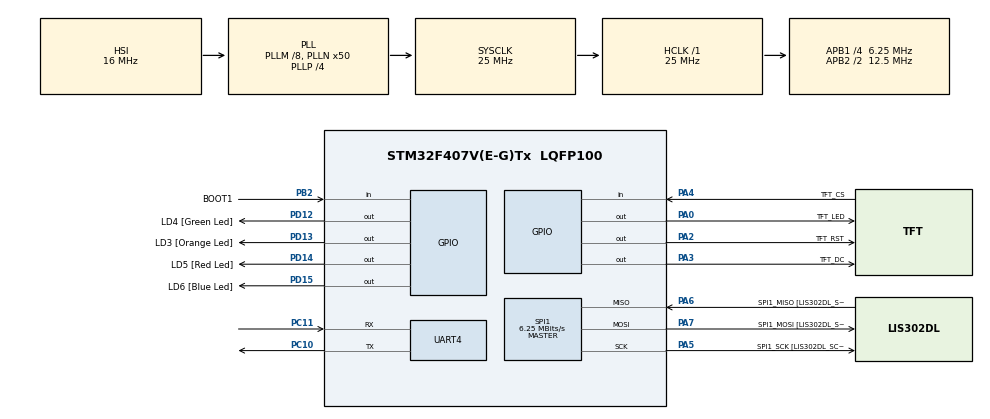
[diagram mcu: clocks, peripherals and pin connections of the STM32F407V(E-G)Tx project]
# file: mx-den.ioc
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Dma.Request0=SPI1_RX
Dma.Request1=SPI1_TX
Dma.SPI1_RX.0.Direction=DMA_PERIPH_TO_MEMORY
Dma.SPI1_RX.0.FIFOMode=DMA_FIFOMODE_DISABLE
Dma.SPI1_RX.0.Instance=DMA2_Stream2
Dma.SPI1_RX.0.MemDataAlignment=DMA_MDATAALIGN_BYTE
Dma.SPI1_RX.0.MemInc=DMA_MINC_ENABLE
Dma.SPI1_RX.0.Mode=DMA_NORMAL
Dma.SPI1_RX.0.PeriphDataAlignment=DMA_PDATAALIGN_BYTE
Dma.SPI1_RX.0.PeriphInc=DMA_PINC_DISABLE
Dma.SPI1_RX.0.Priority=DMA_PRIORITY_LOW
Dma.SPI1_TX.1.Direction=DMA_MEMORY_TO_PERIPH
Dma.SPI1_TX.1.FIFOMode=DMA_FIFOMODE_DISABLE
Dma.SPI1_TX.1.Instance=DMA2_Stream3
Dma.SPI1_TX.1.MemDataAlignment=DMA_MDATAALIGN_BYTE
Dma.SPI1_TX.1.MemInc=DMA_MINC_ENABLE
Dma.SPI1_TX.1.Mode=DMA_NORMAL
Dma.SPI1_TX.1.PeriphDataAlignment=DMA_PDATAALIGN_BYTE
Dma.SPI1_TX.1.PeriphInc=DMA_PINC_DISABLE
Dma.SPI1_TX.1.Priority=DMA_PRIORITY_LOW
Mcu.Family=STM32F4
Mcu.Name=STM32F407V(E-G)Tx
Mcu.Package=LQFP100
NVIC.DMA2_Stream2_IRQn=true\:0\:0\:false\:false\:true\:false\:true\:true
NVIC.DMA2_Stream3_IRQn=true\:0\:0\:false\:false\:true\:false\:true\:true
NVIC.PriorityGroup=NVIC_PRIORITYGROUP_0
NVIC.UART4_IRQn=true\:0\:1\:true\:false\:true\:true\:true\:true
PA0-WKUP.GPIO_Label=TFT_LED
PA0-WKUP.Signal=GPIO_Output
PA2.GPIO_Label=TFT_RST
PA2.Signal=GPIO_Output
PA3.GPIO_Label=TFT_DC
PA3.Signal=GPIO_Output
PA4.GPIO_Label=TFT_CS
PA4.Signal=GPIO_Input
PA5.GPIO_Label=SPI1_SCK [LIS302DL_SCL/SPC]
PA5.GPIO_Mode=GPIO_MODE_AF_PP
PA5.GPIO_PuPd=GPIO_NOPULL
PA5.GPIO_Speed=GPIO_SPEED_FREQ_LOW
PA5.Mode=Full_Duplex_Master
PA5.Signal=SPI1_SCK
PA6.GPIO_Label=SPI1_MISO [LIS302DL_SDO]
PA6.GPIO_Mode=GPIO_MODE_AF_PP
PA6.GPIO_PuPd=GPIO_NOPULL
PA6.GPIO_Speed=GPIO_SPEED_FREQ_LOW
PA6.Mode=Full_Duplex_Master
PA6.Signal=SPI1_MISO
PA7.GPIO_Label=SPI1_MOSI [LIS302DL_SDA/SDI/SDO]
PA7.GPIO_Mode=GPIO_MODE_AF_PP
PA7.GPIO_PuPd=GPIO_NOPULL
PA7.GPIO_Speed=GPIO_SPEED_FREQ_LOW
PA7.Mode=Full_Duplex_Master
PA7.Signal=SPI1_MOSI
PB2.GPIO_Label=BOOT1
PB2.GPIO_Mode=GPIO_MODE_INPUT
PB2.GPIO_PuPd=GPIO_NOPULL
PB2.Signal=GPIO_Input
PC10.Mode=Asynchronous
PC10.Signal=UART4_TX
PC11.Mode=Asynchronous
PC11.Signal=UART4_RX
PC14-OSC32_IN.GPIO_Label=PC14-OSC32_IN
PC14-OSC32_IN.Signal=RCC_OSC32_IN
PC15-OSC32_OUT.GPIO_Label=PC15-OSC32_OUT
PC15-OSC32_OUT.Signal=RCC_OSC32_OUT
PD12.GPIO_Label=LD4 [Green Led]
PD12.GPIO_PuPd=GPIO_NOPULL
PD12.GPIO_Speed=GPIO_SPEED_FREQ_LOW
PD12.Signal=GPIO_Output
PD13.GPIO_Label=LD3 [Orange Led]
PD13.GPIO_PuPd=GPIO_NOPULL
PD13.GPIO_Speed=GPIO_SPEED_FREQ_LOW
PD13.Signal=GPIO_Output
PD14.GPIO_Label=LD5 [Red Led]
PD14.GPIO_PuPd=GPIO_NOPULL
PD14.GPIO_Speed=GPIO_SPEED_FREQ_LOW
PD14.Signal=GPIO_Output
PD15.GPIO_Label=LD6 [Blue Led]
PD15.GPIO_PuPd=GPIO_NOPULL
PD15.GPIO_Speed=GPIO_SPEED_FREQ_LOW
PD15.Signal=GPIO_Output
PH0-OSC_IN.GPIO_Label=PH0-OSC_IN
PH0-OSC_IN.Signal=RCC_OSC_IN
PH1-OSC_OUT.GPIO_Label=PH1-OSC_OUT
PH1-OSC_OUT.Signal=RCC_OSC_OUT
ProjectManager.HeapSize=0x200
ProjectManager.StackSize=0x400
ProjectManager.TargetToolchain=EWARM V8.50
RCC.48MHZClocksFreq_Value=14285714.285714285
RCC.AHBFreq_Value=25000000
RCC.APB1CLKDivider=RCC_HCLK_DIV4
RCC.APB1Freq_Value=6250000
RCC.APB1TimFreq_Value=12500000
RCC.APB2CLKDivider=RCC_HCLK_DIV2
RCC.APB2Freq_Value=12500000
RCC.APB2TimFreq_Value=25000000
RCC.CortexFreq_Value=25000000
RCC.HCLKFreq_Value=25000000
RCC.HSE_VALUE=8000000
RCC.HSI_VALUE=16000000
RCC.LSE_VALUE=32768
RCC.PLLM=8
RCC.PLLN=50
RCC.PLLP=RCC_PLLP_DIV4
RCC.PLLQ=7
RCC.SYSCLKFreq_VALUE=25000000
RCC.SYSCLKSource=RCC_SYSCLKSOURCE_PLLCLK
RCC.VCOOutputFreq_Value=100000000
SPI1.CalculateBaudRate=6.25 MBits/s
SPI1.Direction=SPI_DIRECTION_2LINES
SPI1.Mode=SPI_MODE_MASTER
SPI1.VirtualType=VM_MASTER
UART4.VirtualMode=Asynchronous
board=STM32F407G-DISC1

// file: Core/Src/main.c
/* USER CODE BEGIN Header */
/**
  ******************************************************************************
  * @file           : main.c
  * @brief          : Main program body
  ******************************************************************************
  * @attention
  *
  * Copyright (c) 2022 STMicroelectronics.
  * All rights reserved.
  *
  * This software is licensed under terms that can be found in the LICENSE file
  * in the root directory of this software component.
  * If no LICENSE file comes with this software, it is provided AS-IS.
  *
  ******************************************************************************
  */
/* USER CODE END Header */
#include "main.h"

SPI_HandleTypeDef hspi1;
DMA_HandleTypeDef hdma_spi1_rx;
DMA_HandleTypeDef hdma_spi1_tx;

UART_HandleTypeDef huart4;

void SystemClock_Config(void);
static void MX_GPIO_Init(void);
static void MX_DMA_Init(void);
static void MX_SPI1_Init(void);
static void MX_UART4_Init(void);

int main(void)
{

  /* MCU Configuration--------------------------------------------------------*/

  /* Reset of all peripherals, Initializes the Flash interface and the Systick. */
  HAL_Init();

  /* Configure the system clock */
  SystemClock_Config();

  /* Initialize all configured peripherals */
  MX_GPIO_Init();
  MX_DMA_Init();
  MX_SPI1_Init();
  MX_UART4_Init();

  /* Infinite loop */
  while (1)
  {

  }
}

void SystemClock_Config(void)
{
  RCC_OscInitTypeDef RCC_OscInitStruct = {0};
  RCC_ClkInitTypeDef RCC_ClkInitStruct = {0};

  /** Configure the main internal regulator output voltage
  */
  __HAL_RCC_PWR_CLK_ENABLE();
  __HAL_PWR_VOLTAGESCALING_CONFIG(PWR_REGULATOR_VOLTAGE_SCALE1);

  /** Initializes the RCC Oscillators according to the specified parameters
  * in the RCC_OscInitTypeDef structure.
  */
  RCC_OscInitStruct.OscillatorType = RCC_OSCILLATORTYPE_HSI;
  RCC_OscInitStruct.HSIState = RCC_HSI_ON;
  RCC_OscInitStruct.HSICalibrationValue = RCC_HSICALIBRATION_DEFAULT;
  RCC_OscInitStruct.PLL.PLLState = RCC_PLL_ON;
  RCC_OscInitStruct.PLL.PLLSource = RCC_PLLSOURCE_HSI;
  RCC_OscInitStruct.PLL.PLLM = 8;
  RCC_OscInitStruct.PLL.PLLN = 50;
  RCC_OscInitStruct.PLL.PLLP = RCC_PLLP_DIV4;
  RCC_OscInitStruct.PLL.PLLQ = 7;
  if (HAL_RCC_OscConfig(&RCC_OscInitStruct) != HAL_OK)
  {
    Error_Handler();
  }

  /** Initializes the CPU, AHB and APB buses clocks
  */
  RCC_ClkInitStruct.ClockType = RCC_CLOCKTYPE_HCLK|RCC_CLOCKTYPE_SYSCLK
                              |RCC_CLOCKTYPE_PCLK1|RCC_CLOCKTYPE_PCLK2;
  RCC_ClkInitStruct.SYSCLKSource = RCC_SYSCLKSOURCE_PLLCLK;
  RCC_ClkInitStruct.AHBCLKDivider = RCC_SYSCLK_DIV1;
  RCC_ClkInitStruct.APB1CLKDivider = RCC_HCLK_DIV4;
  RCC_ClkInitStruct.APB2CLKDivider = RCC_HCLK_DIV2;

  if (HAL_RCC_ClockConfig(&RCC_ClkInitStruct, FLASH_LATENCY_0) != HAL_OK)
  {
    Error_Handler();
  }
}

static void MX_SPI1_Init(void)
{

  /* SPI1 parameter configuration*/
  hspi1.Instance = SPI1;
  hspi1.Init.Mode = SPI_MODE_MASTER;
  hspi1.Init.Direction = SPI_DIRECTION_2LINES;
  hspi1.Init.DataSize = SPI_DATASIZE_8BIT;
  hspi1.Init.CLKPolarity = SPI_POLARITY_LOW;
  hspi1.Init.CLKPhase = SPI_PHASE_1EDGE;
  hspi1.Init.NSS = SPI_NSS_SOFT;
  hspi1.Init.BaudRatePrescaler = SPI_BAUDRATEPRESCALER_2;
  hspi1.Init.FirstBit = SPI_FIRSTBIT_MSB;
  hspi1.Init.TIMode = SPI_TIMODE_DISABLE;
  hspi1.Init.CRCCalculation = SPI_CRCCALCULATION_DISABLE;
  hspi1.Init.CRCPolynomial = 10;
  if (HAL_SPI_Init(&hspi1) != HAL_OK)
  {
    Error_Handler();
  }

}

static void MX_UART4_Init(void)
{

  huart4.Instance = UART4;
  huart4.Init.BaudRate = 115200;
  huart4.Init.WordLength = UART_WORDLENGTH_8B;
  huart4.Init.StopBits = UART_STOPBITS_1;
  huart4.Init.Parity = UART_PARITY_NONE;
  huart4.Init.Mode = UART_MODE_TX_RX;
  huart4.Init.HwFlowCtl = UART_HWCONTROL_NONE;
  huart4.Init.OverSampling = UART_OVERSAMPLING_16;
  if (HAL_UART_Init(&huart4) != HAL_OK)
  {
    Error_Handler();
  }

}

static void MX_DMA_Init(void)
{

  /* DMA controller clock enable */
  __HAL_RCC_DMA2_CLK_ENABLE();

  /* DMA interrupt init */
  /* DMA2_Stream2_IRQn interrupt configuration */
  HAL_NVIC_SetPriority(DMA2_Stream2_IRQn, 0, 0);
  HAL_NVIC_EnableIRQ(DMA2_Stream2_IRQn);
  /* DMA2_Stream3_IRQn interrupt configuration */
  HAL_NVIC_SetPriority(DMA2_Stream3_IRQn, 0, 0);
  HAL_NVIC_EnableIRQ(DMA2_Stream3_IRQn);

}

static void MX_GPIO_Init(void)
{
  GPIO_InitTypeDef GPIO_InitStruct = {0};

  /* GPIO Ports Clock Enable */
  __HAL_RCC_GPIOE_CLK_ENABLE();
  __HAL_RCC_GPIOC_CLK_ENABLE();
  __HAL_RCC_GPIOH_CLK_ENABLE();
  __HAL_RCC_GPIOA_CLK_ENABLE();
  __HAL_RCC_GPIOB_CLK_ENABLE();
  __HAL_RCC_GPIOD_CLK_ENABLE();

  /*Configure GPIO pin Output Level */
  HAL_GPIO_WritePin(CS_I2C_SPI_GPIO_Port, CS_I2C_SPI_Pin, GPIO_PIN_RESET);

  /*Configure GPIO pin Output Level */
  HAL_GPIO_WritePin(OTG_FS_PowerSwitchOn_GPIO_Port, OTG_FS_PowerSwitchOn_Pin, GPIO_PIN_SET);

  /*Configure GPIO pin Output Level */
  HAL_GPIO_WritePin(GPIOA, TFT_LED_Pin|TFT_RST_Pin|TFT_DC_Pin, GPIO_PIN_RESET);

  /*Configure GPIO pin Output Level */
  HAL_GPIO_WritePin(GPIOD, LD4_Pin|LD3_Pin|LD5_Pin|LD6_Pin
                          |Audio_RST_Pin, GPIO_PIN_RESET);

  /*Configure GPIO pin : CS_I2C_SPI_Pin */
  GPIO_InitStruct.Pin = CS_I2C_SPI_Pin;
  GPIO_InitStruct.Mode = GPIO_MODE_OUTPUT_PP;
  GPIO_InitStruct.Pull = GPIO_NOPULL;
  GPIO_InitStruct.Speed = GPIO_SPEED_FREQ_LOW;
  HAL_GPIO_Init(CS_I2C_SPI_GPIO_Port, &GPIO_InitStruct);

  /*Configure GPIO pin : OTG_FS_PowerSwitchOn_Pin */
  GPIO_InitStruct.Pin = OTG_FS_PowerSwitchOn_Pin;
  GPIO_InitStruct.Mode = GPIO_MODE_OUTPUT_PP;
  GPIO_InitStruct.Pull = GPIO_NOPULL;
  GPIO_InitStruct.Speed = GPIO_SPEED_FREQ_LOW;
  HAL_GPIO_Init(OTG_FS_PowerSwitchOn_GPIO_Port, &GPIO_InitStruct);

  /*Configure GPIO pin : PDM_OUT_Pin */
  GPIO_InitStruct.Pin = PDM_OUT_Pin;
  GPIO_InitStruct.Mode = GPIO_MODE_AF_PP;
  GPIO_InitStruct.Pull = GPIO_NOPULL;
  GPIO_InitStruct.Speed = GPIO_SPEED_FREQ_LOW;
  GPIO_InitStruct.Alternate = GPIO_AF5_SPI2;
  HAL_GPIO_Init(PDM_OUT_GPIO_Port, &GPIO_InitStruct);

  /*Configure GPIO pins : TFT_LED_Pin TFT_RST_Pin TFT_DC_Pin */
  GPIO_InitStruct.Pin = TFT_LED_Pin|TFT_RST_Pin|TFT_DC_Pin;
  GPIO_InitStruct.Mode = GPIO_MODE_OUTPUT_PP;
  GPIO_InitStruct.Pull = GPIO_NOPULL;
  GPIO_InitStruct.Speed = GPIO_SPEED_FREQ_LOW;
  HAL_GPIO_Init(GPIOA, &GPIO_InitStruct);

  /*Configure GPIO pin : TFT_CS_Pin */
  GPIO_InitStruct.Pin = TFT_CS_Pin;
  GPIO_InitStruct.Mode = GPIO_MODE_INPUT;
  GPIO_InitStruct.Pull = GPIO_NOPULL;
  HAL_GPIO_Init(TFT_CS_GPIO_Port, &GPIO_InitStruct);

  /*Configure GPIO pin : BOOT1_Pin */
  GPIO_InitStruct.Pin = BOOT1_Pin;
  GPIO_InitStruct.Mode = GPIO_MODE_INPUT;
  GPIO_InitStruct.Pull = GPIO_NOPULL;
  HAL_GPIO_Init(BOOT1_GPIO_Port, &GPIO_InitStruct);

  /*Configure GPIO pin : CLK_IN_Pin */
  GPIO_InitStruct.Pin = CLK_IN_Pin;
  GPIO_InitStruct.Mode = GPIO_MODE_AF_PP;
  GPIO_InitStruct.Pull = GPIO_NOPULL;
  GPIO_InitStruct.Speed = GPIO_SPEED_FREQ_LOW;
  GPIO_InitStruct.Alternate = GPIO_AF5_SPI2;
  HAL_GPIO_Init(CLK_IN_GPIO_Port, &GPIO_InitStruct);

  /*Configure GPIO pins : LD4_Pin LD3_Pin LD5_Pin LD6_Pin
                           Audio_RST_Pin */
  GPIO_InitStruct.Pin = LD4_Pin|LD3_Pin|LD5_Pin|LD6_Pin
                          |Audio_RST_Pin;
  GPIO_InitStruct.Mode = GPIO_MODE_OUTPUT_PP;
  GPIO_InitStruct.Pull = GPIO_NOPULL;
  GPIO_InitStruct.Speed = GPIO_SPEED_FREQ_LOW;
  HAL_GPIO_Init(GPIOD, &GPIO_InitStruct);

  /*Configure GPIO pins : I2S3_MCK_Pin I2S3_SD_Pin */
  GPIO_InitStruct.Pin = I2S3_MCK_Pin|I2S3_SD_Pin;
  GPIO_InitStruct.Mode = GPIO_MODE_AF_PP;
  GPIO_InitStruct.Pull = GPIO_NOPULL;
  GPIO_InitStruct.Speed = GPIO_SPEED_FREQ_LOW;
  GPIO_InitStruct.Alternate = GPIO_AF6_SPI3;
  HAL_GPIO_Init(GPIOC, &GPIO_InitStruct);

  /*Configure GPIO pin : VBUS_FS_Pin */
  GPIO_InitStruct.Pin = VBUS_FS_Pin;
  GPIO_InitStruct.Mode = GPIO_MODE_INPUT;
  GPIO_InitStruct.Pull = GPIO_NOPULL;
  HAL_GPIO_Init(VBUS_FS_GPIO_Port, &GPIO_InitStruct);

  /*Configure GPIO pins : OTG_FS_ID_Pin OTG_FS_DM_Pin OTG_FS_DP_Pin */
  GPIO_InitStruct.Pin = OTG_FS_ID_Pin|OTG_FS_DM_Pin|OTG_FS_DP_Pin;
  GPIO_InitStruct.Mode = GPIO_MODE_AF_PP;
  GPIO_InitStruct.Pull = GPIO_NOPULL;
  GPIO_InitStruct.Speed = GPIO_SPEED_FREQ_LOW;
  GPIO_InitStruct.Alternate = GPIO_AF10_OTG_FS;
  HAL_GPIO_Init(GPIOA, &GPIO_InitStruct);

  /*Configure GPIO pin : OTG_FS_OverCurrent_Pin */
  GPIO_InitStruct.Pin = OTG_FS_OverCurrent_Pin;
  GPIO_InitStruct.Mode = GPIO_MODE_INPUT;
  GPIO_InitStruct.Pull = GPIO_NOPULL;
  HAL_GPIO_Init(OTG_FS_OverCurrent_GPIO_Port, &GPIO_InitStruct);

  /*Configure GPIO pins : Audio_SCL_Pin Audio_SDA_Pin */
  GPIO_InitStruct.Pin = Audio_SCL_Pin|Audio_SDA_Pin;
  GPIO_InitStruct.Mode = GPIO_MODE_AF_OD;
  GPIO_InitStruct.Pull = GPIO_NOPULL;
  GPIO_InitStruct.Speed = GPIO_SPEED_FREQ_LOW;
  GPIO_InitStruct.Alternate = GPIO_AF4_I2C1;
  HAL_GPIO_Init(GPIOB, &GPIO_InitStruct);

  /*Configure GPIO pin : MEMS_INT2_Pin */
  GPIO_InitStruct.Pin = MEMS_INT2_Pin;
  GPIO_InitStruct.Mode = GPIO_MODE_EVT_RISING;
  GPIO_InitStruct.Pull = GPIO_NOPULL;
  HAL_GPIO_Init(MEMS_INT2_GPIO_Port, &GPIO_InitStruct);

}

void Error_Handler(void)
{
  __disable_irq();
  while (1)
  {
  }
}
